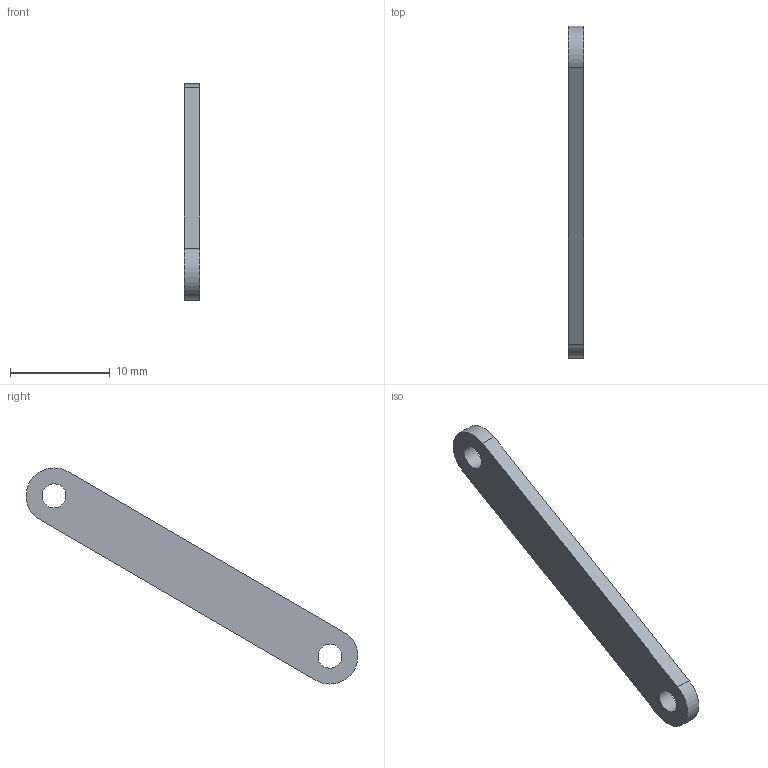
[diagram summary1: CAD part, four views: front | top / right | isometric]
STEP (ISO 10303-21) file: header records copied from the file, then geometry measured from it (millimetres).
FILE_DESCRIPTION(('Open CASCADE Model'),'2;1');
FILE_NAME('Open CASCADE Shape Model','2026-09-30T23:04:27',('Author'),( 'Open CASCADE'),'Open CASCADE STEP processor 8.0','Open CASCADE 8.0' ,'Unknown');
FILE_SCHEMA(('AP242_MANAGED_MODEL_BASED_3D_ENGINEERING_MIM_LF {1 0 10303 442 1 1 4 }' ));
Length unit declared in the file: millimetre
Products named in the file (1): Open CASCADE STEP translator 8.0 6
Bounding box: 1.6 x 33.3 x 21.7 mm (x, y, z)
Volume: 312 mm3; surface area: 544.8 mm2
Topology: 1 solids, 1 shells, 8 faces, 18 edges, 12 vertices
Faces by surface type: plane 4, cylinder 4
Full cylindrical faces by diameter (mm): 2.4 x2
Entity records: 486 total; most frequent: CARTESIAN_POINT 89, DIRECTION 76, ORIENTED_EDGE 36, LINE 36, VECTOR 36, PCURVE 36, DEFINITIONAL_REPRESENTATION 36, EDGE_CURVE 18
